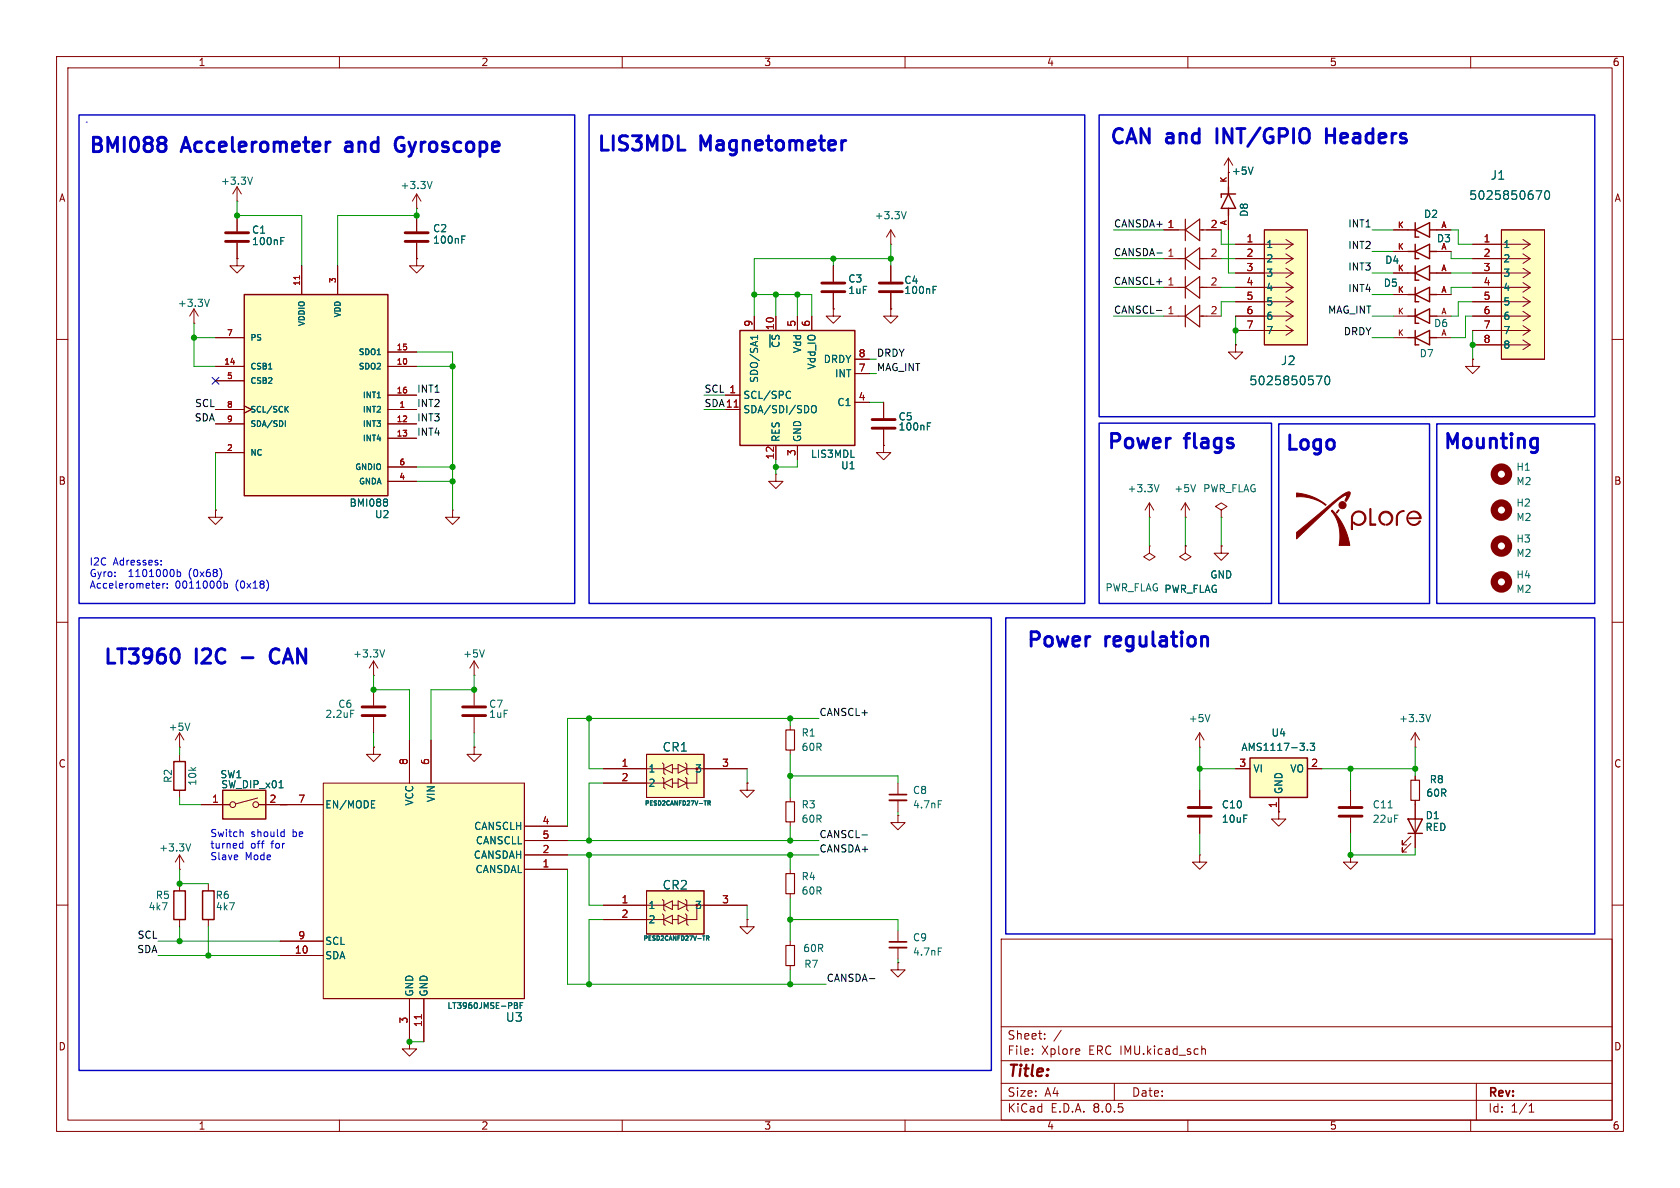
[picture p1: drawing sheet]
<svg xmlns="http://www.w3.org/2000/svg" width="297mm" height="210mm" viewBox="0 0 297 210" stroke-linecap="round" stroke-linejoin="round" font-family="sans-serif">
<defs><g id="words">
<g font-size="3.5" fill="#0000c2">
<text x="15.4" y="27.7">BMI088</text>
<text x="32.3" y="27.7">Accelerometer</text>
<text x="62.1" y="27.7">and</text>
<text x="71.9" y="27.7">Gyroscope</text>
<text x="105.2" y="27.4">LIS3MDL</text>
<text x="123.8" y="27.4">Magnetometer</text>
<text x="195.9" y="26.2">CAN</text>
<text x="206.2" y="26.2">and</text>
<text x="216.1" y="26.2">INT/GPIO</text>
<text x="236.4" y="26.2">Headers</text>
<text x="195.6" y="79.5">Power</text>
<text x="209.8" y="79.5">flags</text>
<text x="227.1" y="79.8">Logo</text>
<text x="255" y="79.5">Mounting</text>
<text x="18" y="118.1">LT3960</text>
<text x="34.6" y="118.1">I2C</text>
<text x="49.8" y="118.1">CAN</text>
<text x="181.4" y="114.6">Power</text>
<text x="195.6" y="114.6">regulation</text>
</g>
<text font-size="2.8" fill="#840000" x="178" y="190.9">Title:</text>
<g font-size="2.1" fill="#006464">
<text x="259.6" y="35.5">5025850670</text>
<text x="263.5" y="32">J1</text>
<text x="226.4" y="64.7">J2</text>
<text x="220.8" y="68.3">5025850570</text>
<text x="117.1" y="133.1">CR1</text>
<text x="117.1" y="157.5">CR2</text>
<text x="89.3" y="180.8">U3</text>
</g>
<g font-size="2.1" fill="#840000">
<text x="178" y="184">Sheet:</text>
<text x="178" y="186.7">File:</text>
<text x="184.1" y="186.7">Xplore</text>
<text x="192.5" y="186.7">ERC IMU.kicad_sch</text>
<text x="178" y="196.9">KiCad</text>
<text x="178" y="194.1">Size:</text>
<text x="184.7" y="194.1">A4</text>
<text x="185.7" y="196.9">E.D.A.</text>
<text x="193.3" y="196.9">8.0.5</text>
<text x="200" y="194.1">Date:</text>
<text x="263" y="194.3">Rev:</text>
<text x="263" y="196.9">Id:</text>
<text x="267.1" y="196.9">1/1</text>
</g>
<g font-size="1.8" fill="#840000">
<text x="35" y="11.9">1</text>
<text x="85" y="11.9">2</text>
<text x="135" y="11.9">3</text>
<text x="185" y="11.9">4</text>
<text x="235" y="11.9">5</text>
<text x="285" y="11.9">6</text>
<text x="10.3" y="35.9">A</text>
<text x="217.7" y="31.1">+5V</text>
<text x="285.3" y="35.9">A</text>
<text x="10.3" y="85.9">B</text>
<text x="285.3" y="85.9">B</text>
<text x="10.3" y="135.9">C</text>
<text x="285.3" y="135.9">C</text>
<text x="10.3" y="185.9">D</text>
<text x="285.3" y="185.9">D</text>
<text x="35" y="199.9">1</text>
<text x="85" y="199.9">2</text>
<text x="135" y="199.9">3</text>
<text x="185" y="199.9">4</text>
<text x="235" y="199.9">5</text>
<text x="285" y="199.9">6</text>
</g>
<g font-size="1.8" fill="#006464">
<text x="39" y="32.9">+3.3V</text>
<text x="70.7" y="33.6">+3.3V</text>
<text x="44.5" y="41.5">C1</text>
<text x="76.5" y="41.2">C2</text>
<text x="154.5" y="39">+3.3V</text>
<text x="220.8" y="38.4" transform="rotate(-90 220.8 38.4)">D8</text>
<text x="251.6" y="38.7">D2</text>
<text x="44.5" y="43.5">100nF</text>
<text x="76.5" y="43.3">100nF</text>
<text x="223.8" y="44">1</text>
<text x="223.8" y="46.6">2</text>
<text x="244.8" y="46.8">D4</text>
<text x="253.9" y="43">D3</text>
<text x="265.7" y="44">1</text>
<text x="265.7" y="46.6">2</text>
<text x="149.9" y="50.1">C3</text>
<text x="149.9" y="52.2">1uF</text>
<text x="159.8" y="50.4">C4</text>
<text x="159.8" y="52.2">100nF</text>
<text x="223.8" y="49.1">3</text>
<text x="223.8" y="51.7">4</text>
<text x="244.5" y="50.9">D5</text>
<text x="265.7" y="49.1">3</text>
<text x="265.7" y="51.7">4</text>
<text x="31.3" y="54.5">+3.3V</text>
<text x="223.8" y="54.2">5</text>
<text x="223.8" y="56.7">6</text>
<text x="223.8" y="59.3">7</text>
<text x="253.4" y="58">D6</text>
<text x="265.7" y="54.2">5</text>
<text x="265.7" y="56.7">6</text>
<text x="265.7" y="59.3">7</text>
<text x="138" y="61.6" transform="rotate(-90 138 61.6)">~{CS}</text>
<text x="141.8" y="62.5" transform="rotate(-90 141.8 62.5)">Vdd</text>
<text x="144.4" y="65.4" transform="rotate(-90 144.4 65.4)">Vdd_IO</text>
<text x="145.5" y="64.4">DRDY</text>
<text x="250.9" y="63.3">D7</text>
<text x="265.7" y="61.8">8</text>
<text x="131.3" y="70.7">SCL/SPC</text>
<text x="134.2" y="67.8" transform="rotate(-90 134.2 67.8)">SDO/SA1</text>
<text x="147.5" y="66.9">INT</text>
<text x="147.9" y="72">C1</text>
<text x="131.3" y="73.3">SDA/SDI/SDO</text>
<text x="158.8" y="74.5">C5</text>
<text x="158.8" y="76.3">100nF</text>
<text x="138" y="78.2" transform="rotate(-90 138 78.2)">RES</text>
<text x="141.8" y="78.2" transform="rotate(-90 141.8 78.2)">GND</text>
<text x="143.3" y="81.1">LIS3MDL</text>
<text x="148.6" y="83.2">U1</text>
<text x="268" y="83.4">H1</text>
<text x="61.7" y="89.8">BMI088</text>
<text x="199.2" y="87.2">+3.3V</text>
<text x="207.5" y="87.2">+5V</text>
<text x="212.6" y="87.2">PWR_FLAG</text>
<text x="268" y="86">M2</text>
<text x="268" y="89.8">H2</text>
<text x="66.2" y="91.8">U2</text>
<text x="268" y="92.3">M2</text>
<text x="268" y="96.1">H3</text>
<text x="268" y="98.7">M2</text>
<text x="195.3" y="104.7">PWR_FLAG PWR_FLAG</text>
<text x="205.7" y="105">PWR_FLAG</text>
<text x="213.9" y="102.5">GND</text>
<text x="268" y="102.5">H4</text>
<text x="268" y="105">M2</text>
<text x="62.3" y="116.4">+3.3V</text>
<text x="81.8" y="116.4">+5V</text>
<text x="59.7" y="125.3">C6</text>
<text x="86.4" y="125.3">C7</text>
<text x="29.7" y="129.4">+5V</text>
<text x="57.4" y="127.1">2.2uF</text>
<text x="86.4" y="127.1">1uF</text>
<text x="141.6" y="130.4">R1</text>
<text x="210.1" y="127.9">+5V</text>
<text x="224.7" y="130.4">U4</text>
<text x="247.2" y="127.9">+3.3V</text>
<text x="38.9" y="137.8">SW1</text>
<text x="114.6" y="136.8">1</text>
<text x="122.8" y="136.8">3</text>
<text x="141.6" y="132.9">60R</text>
<text x="219.4" y="132.9">AMS1117-3.3</text>
<text x="221.5" y="136.8">VI</text>
<text x="228" y="136.8">VO</text>
<text x="30.6" y="138.5" transform="rotate(-90 30.6 138.5)">R2</text>
<text x="34.9" y="139" transform="rotate(-90 34.9 139)">10k</text>
<text x="39" y="139.5">SW_DIP_x01</text>
<text x="57.4" y="143.1">EN/MODE</text>
<text x="73.3" y="142.5" transform="rotate(-90 73.3 142.5)">VCC</text>
<text x="77.1" y="141.9" transform="rotate(-90 77.1 141.9)">VIN</text>
<text x="114.6" y="139.3">2</text>
<text x="141.6" y="143.1">R3</text>
<text x="161.3" y="140.6">C8</text>
<text x="161.3" y="143.1">4.7nF</text>
<text x="215.9" y="143.1">C10</text>
<text x="226.9" y="140.5" transform="rotate(-90 226.9 140.5)">GND</text>
<text x="242.6" y="143.1">C11</text>
<text x="252.1" y="141">60R</text>
<text x="252.7" y="138.7">R8</text>
<text x="83.7" y="146.9">CANSCLH</text>
<text x="84" y="149.5">CANSCLL</text>
<text x="141.6" y="145.6">60R</text>
<text x="215.9" y="145.6">10uF</text>
<text x="242.6" y="145.6">22uF</text>
<text x="251.9" y="147.1">RED</text>
<text x="251.9" y="145">D1</text>
<text x="28" y="150.7">+3.3V</text>
<text x="83.7" y="152">CANSDAH</text>
<text x="84" y="154.5">CANSDAL</text>
<text x="141.6" y="155.8">R4</text>
<text x="26.2" y="161.1">4k7</text>
<text x="27.4" y="159.1">R5</text>
<text x="38" y="159.1">R6</text>
<text x="38.1" y="161.1">4k7</text>
<text x="114.6" y="160.9">1</text>
<text x="122.8" y="160.9">3</text>
<text x="141.6" y="158.3">60R</text>
<text x="57.4" y="167.2">SCL</text>
<text x="114.6" y="163.4">2</text>
<text x="161.3" y="166.6">C9</text>
<text x="57.4" y="169.8">SDA</text>
<text x="141.9" y="168.5">60R</text>
<text x="142.1" y="171.3">R7</text>
<text x="161.3" y="169.1">4.7nF</text>
<text x="73.3" y="176.3" transform="rotate(-90 73.3 176.3)">GND</text>
<text x="75.8" y="176.3" transform="rotate(-90 75.8 176.3)">GND</text>
</g>
<g font-size="1.8" fill="#0f0f0f">
<text x="196.8" y="40.3">CANSDA+ 1</text>
<text x="238.3" y="40.3">INT1</text>
<text x="196.8" y="45.4">CANSDA-</text>
<text x="238.3" y="44.1">INT2</text>
<text x="238.3" y="47.9">INT3</text>
<text x="196.8" y="50.5">CANSCL+</text>
<text x="238.3" y="51.7">INT4</text>
<text x="196.8" y="55.5">CANSCL-</text>
<text x="234.7" y="55.5">MAG_INT</text>
<text x="237.5" y="59.3">DRDY</text>
<text x="154.9" y="63.2">DRDY</text>
<text x="154.9" y="65.7">MAG_INT</text>
<text x="73.7" y="69.5">INT1</text>
<text x="124.5" y="69.5">SCL 1</text>
<text x="34.3" y="74.6">SDA</text>
<text x="34.4" y="72">SCL</text>
<text x="73.7" y="72">INT2</text>
<text x="73.7" y="74.6">INT3</text>
<text x="73.7" y="77.1">INT4</text>
<text x="124.5" y="72">SDA11</text>
<text x="144.8" y="126.7">CANSCL+</text>
<text x="144.8" y="148.2">CANSCL-</text>
<text x="144.8" y="150.8">CANSDA+</text>
<text x="24.2" y="166">SCL</text>
<text x="24.2" y="168.6">SDA</text>
<text x="146" y="173.6">CANSDA-</text>
</g>
<g font-size="1.8" fill="#a90000">
<text x="206.3" y="40.4">1</text>
<text x="213.9" y="40.4">2</text>
<text x="206.3" y="45.5">1</text>
<text x="213.9" y="45.5">2</text>
<text x="220.3" y="42.9">1</text>
<text x="220.3" y="45.5">2</text>
<text x="262.2" y="42.9">1</text>
<text x="262.2" y="45.5">2</text>
<text x="206.3" y="50.5">1</text>
<text x="213.9" y="50.5">2</text>
<text x="220.3" y="48">3</text>
<text x="220.3" y="50.5">4</text>
<text x="220.3" y="53.1">5</text>
<text x="262.2" y="48">3</text>
<text x="262.2" y="50.5">4</text>
<text x="262.2" y="53.1">5</text>
<text x="133.1" y="57.9" transform="rotate(-90 133.1 57.9)">9</text>
<text x="136.9" y="58.5" transform="rotate(-90 136.9 58.5)">10</text>
<text x="140.7" y="57.9" transform="rotate(-90 140.7 57.9)">5</text>
<text x="143.3" y="57.9" transform="rotate(-90 143.3 57.9)">6</text>
<text x="206.3" y="55.6">1</text>
<text x="213.9" y="55.6">2</text>
<text x="220.3" y="55.6">6</text>
<text x="220.3" y="58.2">7</text>
<text x="262.2" y="55.6">6</text>
<text x="262.2" y="58.2">7</text>
<text x="151.7" y="65.8">7</text>
<text x="151.7" y="63.2">8</text>
<text x="262.2" y="60.7">8</text>
<text x="128.8" y="69.6">1</text>
<text x="151.7" y="70.9">4</text>
<text x="128.2" y="72.1">11</text>
<text x="136.9" y="81.3" transform="rotate(-90 136.9 81.3)">12</text>
<text x="140.7" y="80.7" transform="rotate(-90 140.7 80.7)">3</text>
<text x="72.1" y="135.3" transform="rotate(-90 72.1 135.3)">8</text>
<text x="75.9" y="135.3" transform="rotate(-90 75.9 135.3)">6</text>
<text x="109.8" y="135.6">1</text>
<text x="127.6" y="135.6">3</text>
<text x="219" y="135.6">3</text>
<text x="231.7" y="135.6">2</text>
<text x="37.4" y="142">1</text>
<text x="47.6" y="142">2</text>
<text x="52.6" y="142">7</text>
<text x="109.8" y="138.2">2</text>
<text x="225.8" y="142.9" transform="rotate(-90 225.8 142.9)">1</text>
<text x="95.8" y="145.8">4</text>
<text x="95.8" y="148.3">5</text>
<text x="95.8" y="153.4">1</text>
<text x="95.8" y="150.9">2</text>
<text x="109.8" y="159.8">1</text>
<text x="127.6" y="159.8">3</text>
<text x="52.6" y="166.1">9</text>
<text x="109.8" y="162.3">2</text>
<text x="52" y="168.7">10</text>
<text x="72.1" y="181" transform="rotate(-90 72.1 181)">3</text>
<text x="74.7" y="181.7" transform="rotate(-90 74.7 181.7)">11</text>
</g>
<g font-size="1.8" fill="#0000c2">
<text x="15.7" y="100.2">I2C</text>
<text x="20" y="100.2">Adresses:</text>
<text x="15.7" y="102.2">Gyro:</text>
<text x="15.7" y="104.3">Accelerometer:</text>
<text x="22.9" y="102.2">1101000b</text>
<text x="30.9" y="104.3">0011000b</text>
<text x="33.7" y="102.2">(0x68)</text>
<text x="41.7" y="104.3">(0x18)</text>
<text x="37.1" y="148.2">Switch</text>
<text x="44.4" y="148.2">should</text>
<text x="51.8" y="148.2">be</text>
<text x="37.1" y="150.2">turned</text>
<text x="37.1" y="152.3">Slave</text>
<text x="43.3" y="152.3">Mode</text>
<text x="44.3" y="150.2">off</text>
<text x="48.1" y="150.2">for</text>
</g>
<g font-size="1.4" fill="#a90000">
<text x="216.9" y="32.4" transform="rotate(-90 216.9 32.4)">K</text>
<text x="216.9" y="39.9" transform="rotate(-90 216.9 39.9)">A</text>
<text x="247" y="40.4">K</text>
<text x="254.7" y="40.4">A</text>
<text x="247" y="44.2">K</text>
<text x="254.7" y="44.2">A</text>
<text x="53.1" y="50.6" transform="rotate(-90 53.1 50.6)">11</text>
<text x="59.4" y="50.1" transform="rotate(-90 59.4 50.1)">3</text>
<text x="247" y="51.8">K</text>
<text x="247" y="48">K</text>
<text x="254.7" y="51.8">A</text>
<text x="254.7" y="48">A</text>
<text x="40" y="59.4">7</text>
<text x="247" y="59.4">K</text>
<text x="247" y="55.6">K</text>
<text x="254.7" y="59.4">A</text>
<text x="254.7" y="55.6">A</text>
<text x="39.5" y="64.5">14</text>
<text x="70" y="64.5">10</text>
<text x="70" y="62">15</text>
<text x="40" y="67.1">5</text>
<text x="70" y="69.6">16</text>
<text x="40" y="72.1">8</text>
<text x="40" y="74.7">9</text>
<text x="70" y="74.7">12</text>
<text x="70" y="77.2">13</text>
<text x="70.5" y="72.1">1</text>
<text x="40" y="79.8">2</text>
<text x="70.5" y="82.3">6</text>
<text x="70.5" y="84.8">4</text>
</g>
<g font-size="1.4" fill="#006464">
<text x="54.1" y="57.8" transform="rotate(-90 54.1 57.8)">VDDIO</text>
<text x="60.4" y="56.2" transform="rotate(-90 60.4 56.2)">VDD</text>
<text x="44.2" y="65.5">CSB1</text>
<text x="44.2" y="60.4">PS</text>
<text x="63.3" y="65.5">SDO2</text>
<text x="63.3" y="63">SDO1</text>
<text x="44.2" y="68">CSB2</text>
<text x="64" y="70.6">INT1</text>
<text x="44.2" y="73.1">SCL/SCK</text>
<text x="44.2" y="75.7">SDA/SDI</text>
<text x="64" y="73.1">INT2</text>
<text x="64" y="75.7">INT3</text>
<text x="44.2" y="80.7">NC</text>
<text x="62.7" y="83.3">GNDIO</text>
<text x="64" y="78.2">INT4</text>
<text x="63.3" y="85.8">GNDA</text>
<text x="79" y="178.5">LT3960JMSE-PBF</text>
</g>
<g font-size="1.1" fill="#006464">
<text x="113.9" y="142.6">PESD2CANFD27V-TR</text>
<text x="113.6" y="166.5">PESD2CANFD27V-TR</text>
</g>
</g></defs>
<g fill="none" stroke="#840000" stroke-width=".18">
<path d="M10 10h277v190h-277zM12 12h273v186h-273zM60 10v2M110 10v2M160 10v2M210 10v2M260 10v2M10 60h2M246.4 52.1h2.5M254 52.1h2.5M285 60h2M218.4 61v1.2h1.3l-1.3 1.3-1.2-1.3h1.2"/>
<path d="M218.4 61h.1M260.3 63.5v1.3h1.3l-1.3 1.2-1.2-1.2h1.2M260.3 63.5h.1M10 110h2M285 110h2M31.7 133.4v1.2M31.7 139.7v1.3M10 160h2M31.7 153.7h.1M31.7 151.1v2.6M31.7 151.1l-.7 1.3M31.7 151.1l.8 1.3"/>
<path d="M285 160h2M177 166h108v32h-108zM60 198v2M110 198v2M160 198v2M177 194.5h108M177 191.5h108M177 187.5h108M177 181.5h108M182.5 186.3v.1M182.5 185.5v.1M184.7 183.6v.1"/>
<path d="M184.7 182.8v.1M187.6 182.1l-1.3 2M190.7 185.4l.2 .4-.7 .1M190.8 186.3l-.1 .1M197 191.5v3M210 198v2M212.5 185.5l.2-.1 .3 .1 .1 .9M260 198v2M261 191.5v6.5M270.3 196.6h.9M270.3 195.5l.4-.4v1.5"/>
</g>
<path d="M248.9 52.1h1.3M250.2 52.1l2.5-1.3v2.5zM250.2 50.8v2.5h.6M252.7 52.1h1.3M30.7 134.6h2.1v5.1h-2.1z" fill="none" stroke="#840000" stroke-width=".25"/>
<path d="M33.7 149.2l-.4 1.2" fill="none" stroke="#006464" stroke-width=".18"/>
<path d="M231.1 40.6v20.4" fill="none" stroke="#ffffc2" stroke-width=".18"/>
<path d="M223.5 40.6h7.6v20.4h-7.6z" fill="#ffffc2"/>
<g fill="none" stroke="#840000" stroke-width=".18">
<path d="M41.9 35.6h.1M41.9 33l-.8 1.3M41.9 33v2.6M41.9 38.1v2.8M41.9 33l.8 1.3M34.3 57.2h.1M34.3 54.6l-.8 1.3M34.3 54.6v2.6M34.3 54.6l.8 1.3M41.9 45.7v1.3h1.3l-1.3 1.3-1.3-1.3h1.3M41.9 45.7h.1M41.9 42.9v2.8"/>
<path d="M218.4 58.4h10.2M218.4 55.9h10.2M218.4 53.3h10.2M218.4 50.8h10.2M218.4 48.3h10.2M218.4 45.7h10.2M218.4 43.2h10.2M223.5 40.6h7.6v20.4h-7.6zM227.3 57.6l1.3 .8M227.3 55l1.3 .9M227.3 52.5l1.3 .8M227.3 50l1.3 .8"/>
<path d="M227.3 47.4l1.3 .9M227.3 44.9l1.3 .8M227.3 42.3l1.3 .9M228.6 58.4l-1.3 .9M228.6 55.9l-1.3 .8M228.6 53.3l-1.3 .9M228.6 50.8l-1.3 .8M228.6 48.3l-1.3 .8M228.6 45.7l-1.3 .9M228.6 43.2l-1.3 .8M246.4 48.3h2.5M246.4 40.6h2.5"/>
<path d="M254 48.3h2.5M254 40.6h2.5M38.1 90.2v1.2h1.3l-1.3 1.3-1.3-1.3h1.3M38.1 90.2h.1M80 90.2v1.2h1.3l-1.3 1.3-1.3-1.3h1.3M80 90.2h.1M36.8 156.2v1.3M36.8 162.6v1.2"/>
</g>
<path d="M44.6 31.3l-.4 1.3M37 52.9l-.4 1.3M49.6 42.6h.5M49.6 42h.6M232.7 66.5h1l-.6 1.5M234.4 66.6l.2-.1a.83 .83 0 0 1 .6 .6 .83 .83 0 0 1-.3 .8l-.2 .1a.83 .83 0 0 1-.6-.6 .83 .83 0 0 1 .3-.8z" fill="none" stroke="#006464" stroke-width=".18"/>
<path d="M250.2 39.4v2.5h.6M248.9 48.3h1.3M248.9 40.6h1.3M250.2 48.3l2.5-1.3v2.5zM250.2 40.6l2.5-1.2v2.5zM250.2 47v2.5h.6M252.7 48.3h1.3M252.7 40.6h1.3M35.8 157.5h2v5.1h-2z" fill="none" stroke="#840000" stroke-width=".25"/>
<path d="M39.9 42.7h4M39.9 41.1h4" fill="none" stroke="#840000" stroke-width=".51"/>
<circle cx="265.4" cy="83.8" r="1.27" fill="none" stroke="#840000" stroke-width="1.3"/>
<path d="M39.4 139.7h7.6v5.1h-7.6z" fill="#ffffc2"/>
<g fill="none" stroke="#840000" stroke-width=".18">
<path d="M35.6 142.2h5M45.5 141.1l-3.8 1M45.7 142.2h5.1"/>
<circle cx="41.1" cy="142.2" r=".51"/>
<circle cx="45.2" cy="142.2" r=".51"/>
</g>
<path d="M39.4 139.7h7.6v5.1h-7.6z" fill="none" stroke="#840000" stroke-width=".25"/>
<path d="M49.3 139.3h.8" fill="none" stroke="#006464" stroke-width=".18"/>
<path d="M43.2 52.1h25.4v35.5h-25.4z" fill="#ffffc2"/>
<g fill="none" stroke="#840000" stroke-width=".25">
<path d="M217.2 33v1.3M217.2 36.8v1.3M217.2 34.3l1.2 2.5h-2.5zM218.4 34.3h-2.5v.6M43.2 52.1h25.4v35.5h-25.4zM248.9 59.7h1.3M248.9 44.5h1.3M250.2 59.7l2.5-1.3v2.6zM250.2 44.5l2.5-1.3v2.5zM250.2 58.4v2.6h.6M250.2 43.2v2.5h.6M252.7 59.7h1.3"/>
<path d="M252.7 44.5h1.3M30.7 157.5h2.1v5.1h-2.1z"/>
</g>
<g fill="none" stroke="#840000" stroke-width=".18">
<path d="M73.7 36.8h.1M73.7 34.3l-.8 1.3M73.7 34.3v2.5M73.7 38.1v2.8M73.7 34.3l.7 1.3M217.2 30.5v2.5M217.2 38.1v2.5M38.1 59.7h5.1M53.3 47v5.1M59.7 47v5.1M73.7 45.7v1.3h1.2l-1.2 1.3-1.3-1.3h1.3M73.7 45.7h.1"/>
<path d="M73.7 42.9v2.8M205.7 45.7h2.6M205.7 40.6h2.6M205.7 50.8h2.6M213.4 45.7h2.5M213.4 40.6h2.5M213.4 50.8h2.5M246.4 59.7h2.5M246.4 44.5h2.5M254 59.7h2.5M254 44.5h2.5M38.1 72.4h5.1"/>
<path d="M38.1 64.8h5.1M38.1 74.9h5.1M38.1 67.3h5.1M43.2 71.8l1.2 .6-1.2 .6M68.6 72.4h5.1M68.6 64.8h5.1M68.6 74.9h5.1M68.6 77.5h5.1M68.6 62.2h5.1M68.6 69.9h5.1M38.1 80h5.1M68.6 85.1h5.1"/>
<path d="M68.6 82.6h5.1M66 119.4h.1M66 116.8l-.7 1.3M66 116.8v2.6M66 116.8l.8 1.3M83.8 119.4h.1M83.8 116.8l-.7 1.3M83.8 116.8v2.6M83.8 116.8l.8 1.3M31.7 132.1h.1M31.7 129.5l-.7 1.3M31.7 129.5v2.6"/>
<path d="M31.7 129.5l.8 1.3M66 132.1v1.3h1.3l-1.3 1.2-1.2-1.2h1.2M66 132.1h.1M66 121.9v2.8M66 126.7v2.8M83.8 132.1v1.3h1.3l-1.3 1.2-1.3-1.2h1.3M83.8 132.1h.1M212.1 132.1h.1M212.1 129.5l-.8 1.3M212.1 129.5v2.6M212.1 129.5l.8 1.3M250.2 132.1h.1"/>
<path d="M250.2 129.5l-.8 1.3M250.2 129.5v2.6M250.2 129.5l.8 1.3M31.7 156.2v1.3M212.1 151.1v1.3h1.3l-1.3 1.3-1.3-1.3h1.3M212.1 151.1h.1M31.7 162.6v1.2M139.7 166.4v.7M139.7 170.7v.8M158.7 170.2v1.3h1.3l-1.3 1.2-1.2-1.2h1.2M158.7 170.2h.1M158.7 164.5v2"/>
<path d="M158.7 167.5v2M72.4 184.2v1.2h1.3l-1.3 1.3-1.3-1.3h1.3M72.4 184.2h.1"/>
</g>
<path d="M53 48.8v.5" fill="none" stroke="#a90000" stroke-width=".18"/>
<g fill="none" stroke="#006464" stroke-width=".18">
<path d="M76.4 32.1l-.4 1.2M81.6 42.3h.5M81.6 41.7h.6M50.4 74.4v1M50.5 72.3l.5 .6M51 71.8l-.6 .6M68.3 88.2l.2 .3-.2 .3 .2 .2v.2l-.2 .3M68 114.9l-.4 1.2M85.6 114.9l-.4 1.2M33.6 127.8l-.5 1.3M62 125.5h.6M213.9 126.3l-.4 1.3"/>
<path d="M252.9 126.3l-.4 1.3M165.9 167.6h.6"/>
</g>
<g fill="none" stroke="#840000" stroke-width=".2">
<path d="M209.5 38.7v3.8M208.3 45.7h1.2M208.3 40.6h1.2M208.3 50.8h1.2M209.5 45.7l2.6-1.9v3.8zM209.5 40.6l2.6-1.9v3.8zM209.5 50.8l2.6-1.9v3.8zM209.5 43.8v3.8M209.5 48.9v3.8M212.1 45.7h1.3M212.1 40.6h1.3M212.1 50.8h1.3"/>
<path d="M138.9 167.1h1.6v3.6h-1.6z"/>
</g>
<path d="M71.6 42.7h4.1M71.6 41.1h4.1M64 126.5h4.1M64 125h4.1" fill="none" stroke="#840000" stroke-width=".51"/>
<path d="M157.2 167.5h3.1" fill="none" stroke="#840000" stroke-width=".33"/>
<path d="M157.2 166.5h3.1" fill="none" stroke="#840000" stroke-width=".3"/>
<path d="M92.7 138.4v38.1h-35.6" fill="none" stroke="#ffffc2" stroke-width=".18"/>
<path d="M57.1 138.4h35.6v38.1h-35.6z" fill="#ffffc2"/>
<g fill="none" stroke="#840000" stroke-width=".18">
<path d="M57.1 138.4h35.6v38.1h-35.6zM72.4 130.8v7.6M76.2 130.8v7.6M83.8 121.9v2.8M83.8 126.7v2.8M92.7 138.4v38.1h-35.6M139.7 128.3v.7M139.7 132.6v.8M238.8 139.7v2.8M250.2 137.2v.7M49.5 142.2h7.6M92.7 153.7h7.6"/>
<path d="M92.7 151.1h7.6M92.7 146.1h7.6M92.7 148.6h7.6M238.8 151.1v1.3h1.2l-1.2 1.3-1.3-1.3h1.3M238.8 151.1h.1M238.8 144.5v2.8M249.4 149.1l-1.5 1.5v-.7v.7h.8M249.4 147.8l-1.5 1.6v-.8v.8h.8M250.2 141.5v8.4M49.5 168.9h7.6M49.5 166.4h7.6M72.4 176.5v7.7"/>
<path d="M74.9 176.5v7.7"/>
</g>
<path d="M74.5 179.4v.7" fill="none" stroke="#a90000" stroke-width=".18"/>
<path d="M65.7 142.8h.6M65.7 141.5h.6M245.4 142.8h.7M90.9 177.2l.5 .1 .1 .2-.2 .2M90.9 177.7h.4M91.3 177.7l.2 .2v.3l-.6 .1M91.9 177.7h.4M92.4 177.2h-.5v1.1" fill="none" stroke="#006464" stroke-width=".18"/>
<path d="M81.8 126.5h4.1M81.8 125h4.1M236.7 144.3h4.1M236.7 142.7h4.1" fill="none" stroke="#840000" stroke-width=".51"/>
<path d="M138.9 129h1.6v3.6h-1.6zM249.4 137.9h1.6v3.6h-1.6z" fill="none" stroke="#840000" stroke-width=".2"/>
<path d="M248.9 144.8h2.6l-1.3 2.5zM248.9 147.3h2.6" fill="none" stroke="#840000" stroke-width=".25"/>
<path d="M114.3 157.5h10.2v7.6h-10.2z" fill="none" stroke="#ffffc2" stroke-width=".18"/>
<path d="M114.3 157.5h10.2v7.6h-10.2z" fill="#ffffc2"/>
<g fill="none" stroke="#840000" stroke-width=".18">
<path d="M158.7 138.4v2.1M114.3 157.5h10.2v7.6h-10.2zM117.1 159l.2 .3v1.5l.3 .2M119.9 159.3l1.5 .7-1.5 .8zM121.2 159l.2 .3v1.5l.3 .2M158.7 141.5v2M106.7 162.6h10.6M106.7 160h10.6M117.1 161.5l.2 .3v1.5l.3 .3M117.3 162.6l1.6-.8v1.5zM117.3 160l1.6-.7v1.5zM118.9 162.6h1"/>
<path d="M118.9 160h1M119.9 161.8l1.5 .8-1.5 .7zM121.2 161.5l.2 .3v1.5l.3 .3M121.4 160h10.7M123.2 160v2.6h-1.8M132.1 162.6v1.2h1.2l-1.2 1.3-1.3-1.3h1.3M132.1 162.6h.1"/>
</g>
<path d="M165.9 141.5h.6M124.9 165.8h.4v-.3l-.4-.1v.8M125.1 165.8l.2 .4" fill="none" stroke="#006464" stroke-width=".18"/>
<path d="M157.2 141.5h3.1" fill="none" stroke="#840000" stroke-width=".33"/>
<path d="M157.2 140.5h3.1" fill="none" stroke="#840000" stroke-width=".3"/>
<path d="M114.3 133.4h10.2v7.6h-10.2z" fill="none" stroke="#ffffc2" stroke-width=".18"/>
<path d="M114.3 133.4h10.2v7.6h-10.2z" fill="#ffffc2"/>
<g fill="none" stroke="#840000" stroke-width=".18">
<path d="M106.7 138.4h10.6M106.7 135.9h10.6M114.3 133.4h10.2v7.6h-10.2zM117.1 134.9l.2 .2v1.6l.3 .2M117.1 137.4l.2 .3v1.5l.3 .2M117.3 138.4l1.6-.7v1.5zM117.3 135.9l1.6-.8v1.6zM118.9 138.4h1M118.9 135.9h1M119.9 137.7l1.5 .7-1.5 .8zM119.9 135.1l1.5 .8-1.5 .8zM121.2 137.4l.2 .3v1.5l.3 .2"/>
<path d="M121.2 134.9l.2 .2v1.6l.3 .2M121.4 135.9h10.7M123.2 135.9v2.5h-1.8M132.1 138.4v1.3h1.2l-1.2 1.3-1.3-1.3h1.3M132.1 138.4h.1M139.7 141v.7M139.7 145.3v.8M139.7 153.7v.7M139.7 158v.8M158.7 144.1v1.3h1.3l-1.3 1.3-1.2-1.3h1.2M158.7 144.1h.1"/>
</g>
<path d="M125.1 142l.4-.1v-.3h-.4v.7M125.3 142l.3 .3" fill="none" stroke="#006464" stroke-width=".18"/>
<path d="M138.9 154.4h1.6v3.6h-1.6zM138.9 141.7h1.6v3.6h-1.6z" fill="none" stroke="#840000" stroke-width=".2"/>
<path d="M221 134h10.1v7h-10.1z" fill="#ffffc2"/>
<path d="M221 134h10.1v7h-10.1z" fill="none" stroke="#840000" stroke-width=".25"/>
<g fill="none" stroke="#840000" stroke-width=".18">
<path d="M147.3 54.6v1.3h1.3l-1.3 1.3-1.3-1.3h1.3M147.3 54.6h.1M147.3 47v2.8M147.3 51.8v2.8M157.5 43.2h.1M157.5 54.6v1.3h1.2l-1.2 1.3-1.3-1.3h1.3M157.5 54.6h.1M157.5 40.6l-.8 1.3M157.5 40.6v2.6M157.5 47v2.8M157.5 51.8v2.8M157.5 40.6l.7 1.3"/>
<path d="M156.2 71.1v2.8M156.2 75.9v2.8M137.2 83.8v1.3h1.2l-1.2 1.3-1.3-1.3h1.3M137.2 83.8h.1M212.1 139.7v2.8M218.4 135.9h2.6M231.1 135.9h2.6M212.1 144.5v2.8M226.1 143.5v1.3h1.2l-1.2 1.3-1.3-1.3h1.3M226.1 143.5h.1M226.1 141v2.5"/>
</g>
<path d="M160.2 37.4l-.4 1.3M165 51.2h.4M165 50.6h.6M163.9 75.4h.5M163.9 74.7h.6M231.1 132.5v.2M231.6 131.4h.8l-.4 .5 .3 .1v.5l-.1 .2-.6-.2" fill="none" stroke="#006464" stroke-width=".18"/>
<path d="M145.3 51.6h4.1M145.3 50h4.1M155.4 51.6h4.1M155.4 50h4.1M154.2 75.7h4M154.2 74.2h4M210.1 144.3h4M210.1 142.7h4" fill="none" stroke="#840000" stroke-width=".51"/>
<path d="M130.8 58.4h20.3v20.3h-20.3z" fill="#ffffc2"/>
<path d="M130.8 58.4h20.3v20.3h-20.3zM248.9 55.9h1.3M250.2 55.9l2.5-1.3v2.6zM250.2 54.6v2.6h.6M252.7 55.9h1.3" fill="none" stroke="#840000" stroke-width=".25"/>
<g fill="none" stroke="#840000" stroke-width=".18">
<path d="M217.2 27.9l-.8 1.3M217.2 27.9v2.6M217.2 27.9l.7 1.3M133.3 55.9v2.5M137.2 55.9v2.5M141 55.9v2.5M143.5 55.9v2.5M205.7 55.9h2.6M213.4 55.9h2.5M246.4 55.9h2.5M254 55.9h2.5M128.3 69.9h2.5"/>
<path d="M128.3 72.4h2.5M137.2 78.7v2.6M141 78.7v2.6M151.1 71.1h2.6M151.1 66h2.6M151.1 63.5h2.6M156.2 78.7v1.3h1.3l-1.3 1.3-1.3-1.3h1.3M156.2 78.7h.1M203.2 91.4h.1M203.2 96.5v1.3l1 .6-1 .7-1-.7 1-.6M203.2 96.5h.1M203.2 88.9l-.8 1.3"/>
<path d="M203.2 88.9v2.5M203.2 88.9l.8 1.3M209.5 91.4h.1M209.5 96.5v1.3l1.1 .6-1.1 .7-1-.7 1-.6M209.5 96.5h.1M209.5 88.9l-.7 1.3M209.5 88.9v2.5M209.5 88.9l.8 1.3M215.9 90.2l1-.7-1-.6-1 .6 1 .7v1.2M215.9 91.4h.1M215.9 96.5v1.3h1.3l-1.3 1.3-1.3-1.3h1.3M215.9 96.5h.1"/>
</g>
<path d="M221.5 29.5l-.4 1.3M133.9 59.3v.7M133.9 59.6h-1.2l.3 .3M139.4 69.2l.4 .1M139.8 70.3l-.4 .1M143.5 71.9l.3-.2a.43 .43 0 0 1 .5 .4v.4a.42 .42 0 0 1-.4 .5 .42 .42 0 0 1-.4-.5zM204.9 85.7l-.4 1.2M211.4 85.7l-.5 1.2" fill="none" stroke="#006464" stroke-width=".18"/>
<path d="M129.8 72h.7" fill="none" stroke="#a90000" stroke-width=".18"/>
<g fill="#840000" stroke="#840000" stroke-width=".18">
<path d="M242.2 89.9h.2v2.7h.8v.3h-1z"/>
<path d="M236.6 90.1l.1 .1-.4 .5-.1-.1z"/>
<path d="M247.2 90.6l.7-.3h.3v.1a1.32 1.32 0 0 0-1.2 1.7v.8h-.2v-.9a1.67 1.67 0 0 1 .4-1.4z"/>
<path d="M235.5 90.2a11.4 11.4 0 0 1 3.1 6.2h-1.9l.1-.2a7.3 7.3 0 0 0-1.4-5.9z"/>
<path d="M229.2 87.1l.2 .1a9.5 9.5 0 0 1 5 2l-.1 .1a7.2 7.2 0 0 0-5.1-1.5z"/>
<path d="M239.3 90.7a1.28 1.28 0 0 1 1.8 0 1.28 1.28 0 0 1 0 1.8 1.28 1.28 0 0 1-1.8 0v-.3l.2 .2a1.07 1.07 0 0 0 1.6-.3 1.07 1.07 0 0 0-.6-1.5 1.07 1.07 0 0 0-1.4 .9v2.1h-.2v-1.7a1.46 1.46 0 0 1 .4-1.2z"/>
<path d="M244.1 90.7l.8-.3a1.24 1.24 0 0 1 1.3 1.1 1.24 1.24 0 0 1-1.1 1.3v-.1a1.02 1.02 0 0 0 .8-1.6 1.02 1.02 0 0 0-1.7 0 1.02 1.02 0 0 0 .7 1.6v.1a1.24 1.24 0 0 1-1.1-.8 1.24 1.24 0 0 1 .3-1.3z"/>
<path d="M229.2 94.1l6.9-5.7 1.7-1.2a.56 .56 0 0 1 .9 0l-.6 1.2a.17 .17 0 0 1-.2 .2 .17 .17 0 0 1-.1-.3l.2-.5a.18 .18 0 0 0 0-.2 .18 .18 0 0 0-.2 0l-2.1 1.5-6.5 6.2z"/>
<path d="M249.1 90.7a1.26 1.26 0 0 1 1.4-.3 1.26 1.26 0 0 1 .7 1.3h-2.1v-.2h1.9a1.06 1.06 0 0 0-1.5-.8 1.06 1.06 0 0 0-.3 1.7 1.06 1.06 0 0 0 1.7-.3h.2a1.26 1.26 0 0 1-1.8 .6 1.26 1.26 0 0 1-.2-2z"/>
<circle cx="237.3" cy="89.3" r=".63"/>
</g>
<g fill="none" stroke="#840000" stroke-width="1.3">
<circle cx="265.4" cy="96.5" r="1.27"/>
<circle cx="265.4" cy="90.2" r="1.27"/>
<circle cx="265.4" cy="102.9" r="1.27"/>
</g>
<path d="M208.3 55.9h1.2M209.5 55.9l2.6-1.9v3.8zM209.5 54v3.8M212.1 55.9h1.3" fill="none" stroke="#840000" stroke-width=".2"/>
<path d="M273 40.6v22.9h-7.6" fill="none" stroke="#ffffc2" stroke-width=".18"/>
<path d="M265.4 40.6h7.6v22.9h-7.6z" fill="#ffffc2"/>
<g fill="none" stroke="#840000" stroke-width=".18">
<path d="M41.9 38.1v2.8M73.7 38.1v2.8M217.2 30.5v2.5M217.2 38.1v2.5M38.1 59.7h5.1M41.9 45.7h.1M41.9 42.9v2.8M53.3 47v5.1M59.7 47v5.1M73.7 45.7h.1M73.7 42.9v2.8M133.3 55.9v2.5"/>
<path d="M137.2 55.9v2.5M141 55.9v2.5M143.5 55.9v2.5M147.3 54.6h.1M147.3 47v2.8M147.3 51.8v2.8M157.5 54.6h.1M157.5 47v2.8M157.5 51.8v2.8M205.7 40.6h2.6M213.4 40.6h2.5M218.4 58.4h5.1"/>
<path d="M218.4 55.9h5.1M218.4 53.3h5.1M218.4 50.8h5.1M218.4 48.3h5.1M218.4 45.7h5.1M218.4 43.2h5.1M246.4 48.3h2.5M246.4 40.6h2.5M246.4 52.1h2.5M246.4 44.5h2.5M254 48.3h2.5M254 40.6h2.5"/>
<path d="M254 52.1h2.5M254 44.5h2.5M260.3 58.4h10.2M260.3 55.9h10.2M260.3 53.3h10.2M260.3 50.8h10.2M260.3 48.3h10.2M260.3 45.7h10.2M260.3 43.2h10.2M265.4 40.6h7.6v22.9h-7.6zM269.2 57.6l1.3 .8M269.2 55l1.3 .9"/>
<path d="M269.2 52.5l1.3 .8M269.2 50l1.3 .8M269.2 47.4l1.3 .9M269.2 44.9l1.3 .8M269.2 42.3l1.3 .9M270.5 58.4l-1.3 .9M270.5 55.9l-1.3 .8M270.5 53.3l-1.3 .9M270.5 50.8l-1.3 .8M270.5 48.3l-1.3 .8M270.5 45.7l-1.3 .9M270.5 43.2l-1.3 .8"/>
<path d="M38.1 72.4h5.1M38.1 64.8h5.1M38.1 74.9h5.1M38.1 67.3h5.1M43.2 71.8l1.2 .6-1.2 .6M68.6 72.4h5.1M68.6 64.8h5.1M68.6 74.9h5.1M68.6 77.5h5.1M68.6 62.2h5.1M68.6 69.9h5.1M128.3 72.4h2.5"/>
<path d="M128.3 69.9h2.5M137.2 78.7v2.6M141 78.7v2.6M151.1 63.5h2.6M151.1 71.1h2.6M151.1 66h2.6M156.2 78.7h.1M156.2 71.1v2.8M156.2 75.9v2.8M218.4 61h.1M260.3 63.5h.1M260.3 61h10.2"/>
<path d="M269.2 60.1l1.3 .9M270.5 61l-1.3 .8M38.1 90.2h.1M38.1 80h5.1M68.6 85.1h5.1M68.6 82.6h5.1M209.5 96.5h.1M215.9 96.5h.1M66 132.1h.1M72.4 130.8v7.6M76.2 130.8v7.6M83.8 132.1h.1"/>
<path d="M106.7 135.9h7.6M106.7 138.4h7.6M124.5 135.9h7.6M132.1 138.4h.1M212.1 139.7v2.8M218.4 135.9h2.6M231.1 135.9h2.6M250.2 137.2v.7M35.6 142.2h5M45.7 142.2h11.4M92.7 153.7h7.6M92.7 151.1h7.6"/>
<path d="M92.7 146.1h7.6M92.7 148.6h7.6M212.1 144.5v2.8M226.1 143.5h.1M226.1 141v2.5M250.2 141.5v3.3M250.2 147.3v2.6M49.5 168.9h7.6M49.5 166.4h7.6M72.4 176.5v7.7M74.9 176.5v7.7M106.7 160h7.6"/>
<path d="M106.7 162.6h7.6M124.5 160h7.6M132.1 162.6h.1M72.4 184.2h.1"/>
</g>
<g fill="none" stroke="#006464" stroke-width=".18">
<path d="M221.5 29.5l-.4 1.3M271.6 33.7h1l-.7 1.5M273.3 33.8l.1-.1a.82 .82 0 0 1 .4 1.4l-.2 .1a.82 .82 0 0 1-.4-1.3zM49.6 42.6h.5M49.6 42h.6M81.6 42.3h.5M81.6 41.7h.6M133.9 59.3v.7M133.9 59.6h-1.2l.3 .3M165 51.2h.4M165 50.6h.6M50.4 74.4v1"/>
<path d="M50.5 72.3l.5 .6M51 71.8l-.6 .6M139.4 69.2l.4 .1M139.8 70.3l-.4 .1M143.5 71.9l.3-.2a.43 .43 0 0 1 .5 .4v.4a.42 .42 0 0 1-.4 .5 .42 .42 0 0 1-.4-.5zM163.9 75.4h.5M163.9 74.7h.6M232.7 66.5h1l-.6 1.5M234.4 66.6l.2-.1a.83 .83 0 0 1 .6 .6 .83 .83 0 0 1-.3 .8l-.2 .1a.83 .83 0 0 1-.6-.6 .83 .83 0 0 1 .3-.8zM68.3 88.2l.2 .3-.2 .3 .2 .2v.2l-.2 .3M49.3 139.3h.8M231.1 132.5v.2"/>
<path d="M231.6 131.4h.8l-.4 .5 .3 .1v.5l-.1 .2-.6-.2M65.7 142.8h.6M65.7 141.5h.6M125.1 142l.4-.1v-.3h-.4v.7M125.3 142l.3 .3M90.9 177.2l.5 .1 .1 .2-.2 .2M90.9 177.7h.4M91.3 177.7l.2 .2v.3l-.6 .1M91.9 177.7h.4M92.4 177.2h-.5v1.1M124.9 165.8h.4v-.3l-.4-.1v.8M125.1 165.8l.2 .4"/>
</g>
<path d="M204.4 54.9h1M204.5 44.7h1M152.4 147.6h.9M153.7 173h1" fill="none" stroke="#0f0f0f" stroke-width=".18"/>
<path d="M28.9 24.3a.55 .55 0 0 1 .4 .5 .55 .55 0 0 1-.4 .6l.4 .4v.5l-.4 .5M58.4 25.1l-.5 .1M71.1 24.3a1.13 1.13 0 0 0-1.2 1.4 1.03 1.03 0 0 0 1.1 1.1M149.5 24.8l-.5 .2M234.5 22.7v2.6M234.5 23.9h1.4M31.1 114.7a1.49 1.49 0 0 1 .5 2l-.5 .5M42.8 116.3h1.9M48.9 114.7a1.32 1.32 0 0 0-.9 2.2l.2 .2 .7 .1" fill="none" stroke="#0000c2" stroke-width=".51"/>
<g fill="none" stroke="#0000c2" stroke-width=".18">
<path d="M15.2 21.6h.1M28.5 99.8v.1M28.5 99.1v.1M28.1 103.1l.1 .3-.6 .2M28.2 103.9l-.1 .1M28.8 103.1v.9M29.2 103.1l-.4 .3M29.6 103.9v.1M29.6 103.2v.1M31.3 100.7v1.2M31.3 101.1h.4l.2 .2-.1 .6h-.5M39.1 101v.9"/>
<path d="M39.6 103.2l.4-.1 .2 .3-.1 .5h-.5M39.6 102.7v1.3M47.2 102.6a1.49 1.49 0 0 1 0 1.8M42.6 149.1h.3M42.6 147l.4 .2v.7M42.9 148.7v1.2M42.9 149.9h-.3M49.9 147l.3 .1M50.2 146.6v1.3M50.2 147.8l-.3 .1"/>
</g>
<path d="M14 20.3h87.6v86.4h-87.6zM104.1 20.3h87.7v86.4h-87.7zM194.3 20.3h87.6v53.4h-87.6zM194.3 74.8h30.5v31.9h-30.5zM226.1 74.9h26.6v31.8h-26.6zM254 74.9h27.9v31.8h-27.9zM14 109.2h161.3v80h-161.3zM177.8 109.2h104.1v55.9h-104.1z" fill="none" stroke="#0000c2" stroke-width=".25"/>
<g fill="none" stroke="#009600" stroke-width=".18">
<path d="M41.9 35.6v2.5h11.4v8.9M73.7 36.8v1.3h-14v8.9M34.3 57.2v7.6h3.8M34.3 59.7h3.8M133.3 52.1h10.2v3.8M137.2 52.1v3.8M141 52.1v3.8M147.3 45.7v1.3M157.5 45.7h-24.2v10.2M157.5 43.2v3.8M196.8 45.7h8.9M196.8 50.8h8.9"/>
<path d="M196.8 55.9h8.9M196.8 40.6h8.9M215.9 45.7h2.5M215.9 50.8h2.5M215.9 40.6v2.6h2.5M217.2 40.6v7.7h1.2M218.4 53.3h-2.5v2.6M218.4 55.9v5.1M242.6 52.1h3.8M242.6 55.9h3.8M242.6 59.7h3.8M242.6 48.3h3.8"/>
<path d="M242.6 40.6h3.8M242.6 44.5h3.8M256.5 44.5v1.2h3.8M256.5 40.6h1.3v2.6h2.5M256.5 48.3h3.8M260.3 53.3h-2.5v2.6h-1.3M260.3 50.8h-3.8v1.3M260.3 55.9h-1.2v3.8h-2.6M260.3 58.4v5.1M73.7 62.2h6.3v28M73.7 64.8h6.3M124.5 69.9h3.8"/>
<path d="M124.5 72.4h3.8M153.7 71.1h2.5M153.7 63.5h1.2M153.7 66h1.2M38.1 80v10.2M73.7 82.6h6.3M73.7 85.1h6.3M137.2 81.3v2.5M141 81.3v1.3h-3.8M203.2 91.4v5.1M209.5 91.4v5.1M215.9 91.4v5.1"/>
<path d="M66 119.4v2.5h6.4v8.9M83.8 119.4v2.5h-7.6v8.9M31.7 132.1v1.3M66 129.5v2.6M83.8 129.5v2.6M104.1 127v8.9h2.6M106.7 138.4h-2.6v10.2M132.1 135.9v2.5M139.7 127v1.3M139.7 133.4v7.6M139.7 137.2h19v1.2M144.8 127h-44.5v19.1"/>
<path d="M212.1 135.9h6.3M212.1 132.1v7.6M233.7 135.9h16.5M238.8 135.9v3.8M250.2 132.1v5.1M31.7 141v1.2h3.9M31.7 153.7v2.5h5.1M49.5 142.2h1.3M100.3 153.7v20.3h45.7M100.3 151.1h44.5M100.3 148.6h44.5M104.1 151.1v8.9h2.6"/>
<path d="M139.7 146.1v2.5M139.7 151.1v2.6M139.7 158.8v7.6M158.7 143.5v.6M212.1 147.3v3.8M238.8 147.3v3.8h11.4v-1.2M27.9 166.4h21.6M27.9 168.9h21.6M31.7 163.8v2.6M36.8 163.8v5.1M106.7 162.6h-2.6v11.4M132.1 160v2.6"/>
<path d="M139.7 162.6h19v1.9M139.7 171.5v2.5M158.7 169.5v.7M72.4 184.2h2.5"/>
</g>
<path d="M37.5 66.7l1.2 1.2M38.7 66.7l-1.2 1.2" fill="none" stroke="#000084" stroke-width=".18"/>
<path d="M53 48.8v.5M129.8 72h.7M74.5 179.4v.7" fill="none" stroke="#a90000" stroke-width=".18"/>
<g fill="#009600" stroke="#009600" stroke-width=".18">
<circle cx="31.7" cy="156.2" r=".46"/>
<circle cx="36.8" cy="168.9" r=".46"/>
<circle cx="31.7" cy="166.4" r=".46"/>
<circle cx="72.4" cy="184.2" r=".46"/>
<circle cx="104.1" cy="174" r=".46"/>
<circle cx="139.7" cy="148.6" r=".46"/>
<circle cx="139.7" cy="137.2" r=".46"/>
<circle cx="41.9" cy="38.1" r=".46"/>
<circle cx="34.3" cy="59.7" r=".46"/>
<circle cx="73.7" cy="38.1" r=".46"/>
<circle cx="139.7" cy="162.6" r=".46"/>
<circle cx="139.7" cy="174" r=".46"/>
<circle cx="104.1" cy="151.1" r=".46"/>
<circle cx="104.1" cy="148.6" r=".46"/>
<circle cx="139.7" cy="151.1" r=".46"/>
<circle cx="80" cy="85.1" r=".46"/>
<circle cx="104.1" cy="127" r=".46"/>
<circle cx="66" cy="121.9" r=".46"/>
<circle cx="83.8" cy="121.9" r=".46"/>
<circle cx="80" cy="64.8" r=".46"/>
<circle cx="80" cy="82.6" r=".46"/>
<circle cx="137.2" cy="82.6" r=".46"/>
<circle cx="139.7" cy="127" r=".46"/>
<circle cx="157.5" cy="45.7" r=".46"/>
<circle cx="147.3" cy="45.7" r=".46"/>
<circle cx="141" cy="52.1" r=".46"/>
<circle cx="137.2" cy="52.1" r=".46"/>
<circle cx="133.3" cy="52.1" r=".46"/>
<circle cx="260.3" cy="61" r=".46"/>
<circle cx="218.4" cy="58.4" r=".46"/>
<circle cx="238.8" cy="151.1" r=".46"/>
<circle cx="212.1" cy="135.9" r=".46"/>
<circle cx="238.8" cy="135.9" r=".46"/>
<circle cx="250.2" cy="135.9" r=".46"/>
</g>
<use href="#words"/>
</svg>
